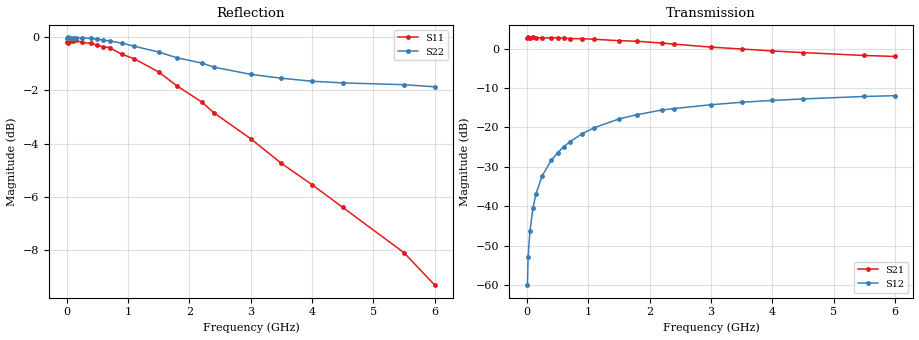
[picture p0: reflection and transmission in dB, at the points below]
! SIEMENS Discrete & RF Semiconductors
! BFY180
! Si NPN RF Bipolar Junction Transistor in MICRO-X
! VCE = 3 V  IC = 0.4 mA
! Common Emitter S-Parameters:  May  1997
# GHz  S  MA  R  50
!  f  S11  S21  S12  S22
! GHz  MAG  ANG  MAG  ANG  MAG  ANG  MAG  ANG
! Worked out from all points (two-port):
!   36 points, 10 MHz to 6 GHz, reference 50 ohm
!   highest |S21| = 2.86 dB at 20 MHz (marker M1); lowest = -2.0 dB at 6 GHz (marker M2)
!   |S21| within 3 dB of the highest: start of sweep to 3.553 GHz
!   lowest |S11| = -9.3 dB at 6 GHz (marker M3), VSWR 2.04, Z = 28.3 - j16.5 ohm
!   |S11| at or under -10 dB: nowhere
!   |S22| runs from -1.9 to 0.0 dB; largest |S21 - S12| = 1.4
!   S11 on the Smith chart (normalised r, x): 10 MHz: open; 700 MHz: 0.64, -5.24; 1.5 GHz: 0.52, -2.39; 2.4 GHz: 0.51, -1.40; 4 GHz: 0.52, -0.75; 6 GHz: 0.57, -0.33
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0.01  0.982 -0.1  1.376 179.9  0.001 87.8  0.9993 -0.2
0.02  0.976 -0.7  1.39 179.0  0.0023 92.7  0.9999 -0.5
0.05  0.983 -1.3  1.373 178.1  0.0048 89.5  0.9994 -1.1
0.1  0.9835 -3.2  1.389 176.3  0.0095 90.0  0.9985 -2.3
0.15  0.9869 -4.8  1.372 174.3  0.0145 86.3  0.9989 -3.2
0.25  0.978 -7.5  1.371 170.6  0.0244 84.5  0.9982 -5.5
0.4  0.9745 -12.3  1.367 164.1  0.0385 80.5  0.9956 -8.7
0.5  0.9662 -15.4  1.378 159.9  0.0476 77.8  0.992 -10.9
0.6  0.9597 -18.2  1.358 155.5  0.057 75.3  0.9885 -13.0
0.7  0.9566 -21.3  1.342 152.7  0.0659 72.9  0.9849 -15.2
0.9  0.9292 -27.1  1.339 145.0  0.0831 68.0  0.9752 -19.4
1.1  0.9117 -32.7  1.314 137.7  0.0993 63.6  0.9626 -23.5
1.5  0.8608 -43.8  1.264 123.5  0.1283 54.8  0.9383 -31.5
1.8  0.81 -52.4  1.241 112.5  0.1454 49.1  0.9153 -36.9
2.2  0.7559 -61.8  1.178 99.3  0.1667 41.6  0.8946 -43.9
2.4  0.7211 -66.6  1.141 93.1  0.1738 38.4  0.8789 -47.1
3  0.6444 -78.8  1.046 76.5  0.1943 29.7  0.8519 -56.0
3.5  0.5792 -87.5  0.99 63.6  0.209 23.9  0.8376 -62.7
4  0.5281 -96.1  0.935 52.3  0.2204 18.1  0.8268 -69.5
4.5  0.4786 -104.0  0.892 41.8  0.2301 13.1  0.8209 -76.3
5.5  0.3931 -121.3  0.819 22.5  0.2475 3.1  0.8145 -90.3
6  0.3416 -130.8  0.797 13.8  0.2531 -1.8  0.8071 -97.4
